VERSION 5.7 ;
BUSBITCHARS "[]" ;
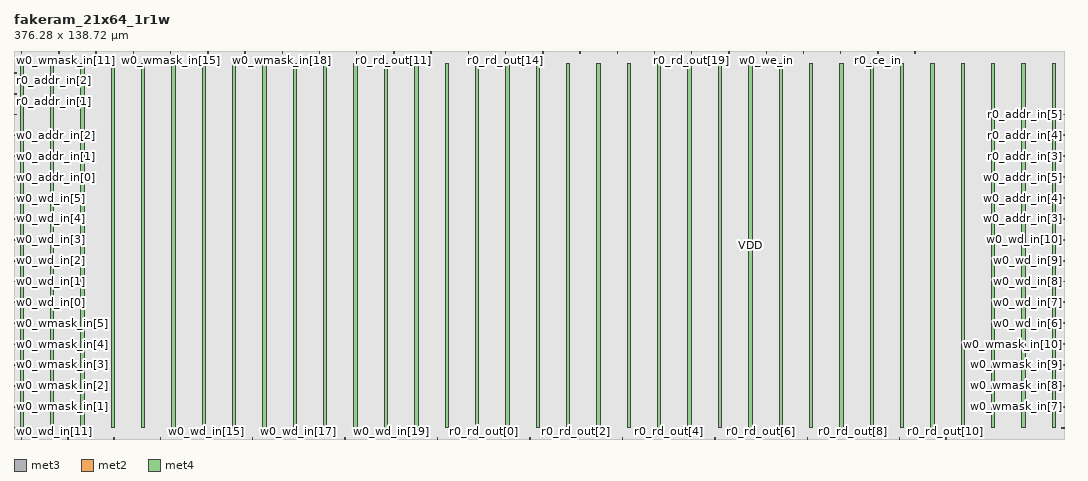
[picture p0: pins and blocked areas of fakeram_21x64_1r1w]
MACRO fakeram_21x64_1r1w
  FOREIGN fakeram_21x64_1r1w 0 0 ;
  SYMMETRY X Y R90 ;
  SIZE 376.280 BY 138.720 ;
  CLASS BLOCK ;
  PIN w0_wmask_in[0]
    DIRECTION INPUT ;
    USE SIGNAL ;
    SHAPE ABUTMENT ;
    PORT
      LAYER met3 ;
      RECT 0.000 3.930 0.900 4.230 ;
    END
  END w0_wmask_in[0]
  PIN w0_wmask_in[1]
    DIRECTION INPUT ;
    USE SIGNAL ;
    SHAPE ABUTMENT ;
    PORT
      LAYER met3 ;
      RECT 0.000 11.410 0.900 11.710 ;
    END
  END w0_wmask_in[1]
  PIN w0_wmask_in[2]
    DIRECTION INPUT ;
    USE SIGNAL ;
    SHAPE ABUTMENT ;
    PORT
      LAYER met3 ;
      RECT 0.000 18.890 0.900 19.190 ;
    END
  END w0_wmask_in[2]
  PIN w0_wmask_in[3]
    DIRECTION INPUT ;
    USE SIGNAL ;
    SHAPE ABUTMENT ;
    PORT
      LAYER met3 ;
      RECT 0.000 26.370 0.900 26.670 ;
    END
  END w0_wmask_in[3]
  PIN w0_wmask_in[4]
    DIRECTION INPUT ;
    USE SIGNAL ;
    SHAPE ABUTMENT ;
    PORT
      LAYER met3 ;
      RECT 0.000 33.850 0.900 34.150 ;
    END
  END w0_wmask_in[4]
  PIN w0_wmask_in[5]
    DIRECTION INPUT ;
    USE SIGNAL ;
    SHAPE ABUTMENT ;
    PORT
      LAYER met3 ;
      RECT 0.000 41.330 0.900 41.630 ;
    END
  END w0_wmask_in[5]
  PIN w0_wmask_in[6]
    DIRECTION INPUT ;
    USE SIGNAL ;
    SHAPE ABUTMENT ;
    PORT
      LAYER met3 ;
      RECT 375.380 3.930 376.280 4.230 ;
    END
  END w0_wmask_in[6]
  PIN w0_wmask_in[7]
    DIRECTION INPUT ;
    USE SIGNAL ;
    SHAPE ABUTMENT ;
    PORT
      LAYER met3 ;
      RECT 375.380 11.410 376.280 11.710 ;
    END
  END w0_wmask_in[7]
  PIN w0_wmask_in[8]
    DIRECTION INPUT ;
    USE SIGNAL ;
    SHAPE ABUTMENT ;
    PORT
      LAYER met3 ;
      RECT 375.380 18.890 376.280 19.190 ;
    END
  END w0_wmask_in[8]
  PIN w0_wmask_in[9]
    DIRECTION INPUT ;
    USE SIGNAL ;
    SHAPE ABUTMENT ;
    PORT
      LAYER met3 ;
      RECT 375.380 26.370 376.280 26.670 ;
    END
  END w0_wmask_in[9]
  PIN w0_wmask_in[10]
    DIRECTION INPUT ;
    USE SIGNAL ;
    SHAPE ABUTMENT ;
    PORT
      LAYER met3 ;
      RECT 375.380 33.850 376.280 34.150 ;
    END
  END w0_wmask_in[10]
  PIN w0_wmask_in[11]
    DIRECTION INPUT ;
    USE SIGNAL ;
    SHAPE ABUTMENT ;
    PORT
      LAYER met2 ;
      RECT 2.690 138.300 2.830 138.720 ;
    END
  END w0_wmask_in[11]
  PIN w0_wmask_in[12]
    DIRECTION INPUT ;
    USE SIGNAL ;
    SHAPE ABUTMENT ;
    PORT
      LAYER met2 ;
      RECT 16.030 138.300 16.170 138.720 ;
    END
  END w0_wmask_in[12]
  PIN w0_wmask_in[13]
    DIRECTION INPUT ;
    USE SIGNAL ;
    SHAPE ABUTMENT ;
    PORT
      LAYER met2 ;
      RECT 29.370 138.300 29.510 138.720 ;
    END
  END w0_wmask_in[13]
  PIN w0_wmask_in[14]
    DIRECTION INPUT ;
    USE SIGNAL ;
    SHAPE ABUTMENT ;
    PORT
      LAYER met2 ;
      RECT 42.710 138.300 42.850 138.720 ;
    END
  END w0_wmask_in[14]
  PIN w0_wmask_in[15]
    DIRECTION INPUT ;
    USE SIGNAL ;
    SHAPE ABUTMENT ;
    PORT
      LAYER met2 ;
      RECT 56.050 138.300 56.190 138.720 ;
    END
  END w0_wmask_in[15]
  PIN w0_wmask_in[16]
    DIRECTION INPUT ;
    USE SIGNAL ;
    SHAPE ABUTMENT ;
    PORT
      LAYER met2 ;
      RECT 69.390 138.300 69.530 138.720 ;
    END
  END w0_wmask_in[16]
  PIN w0_wmask_in[17]
    DIRECTION INPUT ;
    USE SIGNAL ;
    SHAPE ABUTMENT ;
    PORT
      LAYER met2 ;
      RECT 82.730 138.300 82.870 138.720 ;
    END
  END w0_wmask_in[17]
  PIN w0_wmask_in[18]
    DIRECTION INPUT ;
    USE SIGNAL ;
    SHAPE ABUTMENT ;
    PORT
      LAYER met2 ;
      RECT 96.070 138.300 96.210 138.720 ;
    END
  END w0_wmask_in[18]
  PIN w0_wmask_in[19]
    DIRECTION INPUT ;
    USE SIGNAL ;
    SHAPE ABUTMENT ;
    PORT
      LAYER met2 ;
      RECT 109.410 138.300 109.550 138.720 ;
    END
  END w0_wmask_in[19]
  PIN w0_wmask_in[20]
    DIRECTION INPUT ;
    USE SIGNAL ;
    SHAPE ABUTMENT ;
    PORT
      LAYER met2 ;
      RECT 122.750 138.300 122.890 138.720 ;
    END
  END w0_wmask_in[20]
  PIN w0_wd_in[0]
    DIRECTION INPUT ;
    USE SIGNAL ;
    SHAPE ABUTMENT ;
    PORT
      LAYER met3 ;
      RECT 0.000 48.810 0.900 49.110 ;
    END
  END w0_wd_in[0]
  PIN w0_wd_in[1]
    DIRECTION INPUT ;
    USE SIGNAL ;
    SHAPE ABUTMENT ;
    PORT
      LAYER met3 ;
      RECT 0.000 56.290 0.900 56.590 ;
    END
  END w0_wd_in[1]
  PIN w0_wd_in[2]
    DIRECTION INPUT ;
    USE SIGNAL ;
    SHAPE ABUTMENT ;
    PORT
      LAYER met3 ;
      RECT 0.000 63.770 0.900 64.070 ;
    END
  END w0_wd_in[2]
  PIN w0_wd_in[3]
    DIRECTION INPUT ;
    USE SIGNAL ;
    SHAPE ABUTMENT ;
    PORT
      LAYER met3 ;
      RECT 0.000 71.250 0.900 71.550 ;
    END
  END w0_wd_in[3]
  PIN w0_wd_in[4]
    DIRECTION INPUT ;
    USE SIGNAL ;
    SHAPE ABUTMENT ;
    PORT
      LAYER met3 ;
      RECT 0.000 78.730 0.900 79.030 ;
    END
  END w0_wd_in[4]
  PIN w0_wd_in[5]
    DIRECTION INPUT ;
    USE SIGNAL ;
    SHAPE ABUTMENT ;
    PORT
      LAYER met3 ;
      RECT 0.000 86.210 0.900 86.510 ;
    END
  END w0_wd_in[5]
  PIN w0_wd_in[6]
    DIRECTION INPUT ;
    USE SIGNAL ;
    SHAPE ABUTMENT ;
    PORT
      LAYER met3 ;
      RECT 375.380 41.330 376.280 41.630 ;
    END
  END w0_wd_in[6]
  PIN w0_wd_in[7]
    DIRECTION INPUT ;
    USE SIGNAL ;
    SHAPE ABUTMENT ;
    PORT
      LAYER met3 ;
      RECT 375.380 48.810 376.280 49.110 ;
    END
  END w0_wd_in[7]
  PIN w0_wd_in[8]
    DIRECTION INPUT ;
    USE SIGNAL ;
    SHAPE ABUTMENT ;
    PORT
      LAYER met3 ;
      RECT 375.380 56.290 376.280 56.590 ;
    END
  END w0_wd_in[8]
  PIN w0_wd_in[9]
    DIRECTION INPUT ;
    USE SIGNAL ;
    SHAPE ABUTMENT ;
    PORT
      LAYER met3 ;
      RECT 375.380 63.770 376.280 64.070 ;
    END
  END w0_wd_in[9]
  PIN w0_wd_in[10]
    DIRECTION INPUT ;
    USE SIGNAL ;
    SHAPE ABUTMENT ;
    PORT
      LAYER met3 ;
      RECT 375.380 71.250 376.280 71.550 ;
    END
  END w0_wd_in[10]
  PIN w0_wd_in[11]
    DIRECTION OUTPUT ;
    USE SIGNAL ;
    SHAPE ABUTMENT ;
    PORT
      LAYER met2 ;
      RECT 2.690 0.000 2.830 0.420 ;
    END
  END w0_wd_in[11]
  PIN w0_wd_in[12]
    DIRECTION OUTPUT ;
    USE SIGNAL ;
    SHAPE ABUTMENT ;
    PORT
      LAYER met2 ;
      RECT 19.250 0.000 19.390 0.420 ;
    END
  END w0_wd_in[12]
  PIN w0_wd_in[13]
    DIRECTION OUTPUT ;
    USE SIGNAL ;
    SHAPE ABUTMENT ;
    PORT
      LAYER met2 ;
      RECT 35.810 0.000 35.950 0.420 ;
    END
  END w0_wd_in[13]
  PIN w0_wd_in[14]
    DIRECTION OUTPUT ;
    USE SIGNAL ;
    SHAPE ABUTMENT ;
    PORT
      LAYER met2 ;
      RECT 52.370 0.000 52.510 0.420 ;
    END
  END w0_wd_in[14]
  PIN w0_wd_in[15]
    DIRECTION OUTPUT ;
    USE SIGNAL ;
    SHAPE ABUTMENT ;
    PORT
      LAYER met2 ;
      RECT 68.930 0.000 69.070 0.420 ;
    END
  END w0_wd_in[15]
  PIN w0_wd_in[16]
    DIRECTION OUTPUT ;
    USE SIGNAL ;
    SHAPE ABUTMENT ;
    PORT
      LAYER met2 ;
      RECT 85.490 0.000 85.630 0.420 ;
    END
  END w0_wd_in[16]
  PIN w0_wd_in[17]
    DIRECTION OUTPUT ;
    USE SIGNAL ;
    SHAPE ABUTMENT ;
    PORT
      LAYER met2 ;
      RECT 102.050 0.000 102.190 0.420 ;
    END
  END w0_wd_in[17]
  PIN w0_wd_in[18]
    DIRECTION OUTPUT ;
    USE SIGNAL ;
    SHAPE ABUTMENT ;
    PORT
      LAYER met2 ;
      RECT 118.610 0.000 118.750 0.420 ;
    END
  END w0_wd_in[18]
  PIN w0_wd_in[19]
    DIRECTION OUTPUT ;
    USE SIGNAL ;
    SHAPE ABUTMENT ;
    PORT
      LAYER met2 ;
      RECT 135.170 0.000 135.310 0.420 ;
    END
  END w0_wd_in[19]
  PIN w0_wd_in[20]
    DIRECTION OUTPUT ;
    USE SIGNAL ;
    SHAPE ABUTMENT ;
    PORT
      LAYER met2 ;
      RECT 151.730 0.000 151.870 0.420 ;
    END
  END w0_wd_in[20]
  PIN r0_rd_out[0]
    DIRECTION OUTPUT ;
    USE SIGNAL ;
    SHAPE ABUTMENT ;
    PORT
      LAYER met2 ;
      RECT 168.290 0.000 168.430 0.420 ;
    END
  END r0_rd_out[0]
  PIN r0_rd_out[1]
    DIRECTION OUTPUT ;
    USE SIGNAL ;
    SHAPE ABUTMENT ;
    PORT
      LAYER met2 ;
      RECT 184.850 0.000 184.990 0.420 ;
    END
  END r0_rd_out[1]
  PIN r0_rd_out[2]
    DIRECTION OUTPUT ;
    USE SIGNAL ;
    SHAPE ABUTMENT ;
    PORT
      LAYER met2 ;
      RECT 201.410 0.000 201.550 0.420 ;
    END
  END r0_rd_out[2]
  PIN r0_rd_out[3]
    DIRECTION OUTPUT ;
    USE SIGNAL ;
    SHAPE ABUTMENT ;
    PORT
      LAYER met2 ;
      RECT 217.970 0.000 218.110 0.420 ;
    END
  END r0_rd_out[3]
  PIN r0_rd_out[4]
    DIRECTION OUTPUT ;
    USE SIGNAL ;
    SHAPE ABUTMENT ;
    PORT
      LAYER met2 ;
      RECT 234.530 0.000 234.670 0.420 ;
    END
  END r0_rd_out[4]
  PIN r0_rd_out[5]
    DIRECTION OUTPUT ;
    USE SIGNAL ;
    SHAPE ABUTMENT ;
    PORT
      LAYER met2 ;
      RECT 251.090 0.000 251.230 0.420 ;
    END
  END r0_rd_out[5]
  PIN r0_rd_out[6]
    DIRECTION OUTPUT ;
    USE SIGNAL ;
    SHAPE ABUTMENT ;
    PORT
      LAYER met2 ;
      RECT 267.650 0.000 267.790 0.420 ;
    END
  END r0_rd_out[6]
  PIN r0_rd_out[7]
    DIRECTION OUTPUT ;
    USE SIGNAL ;
    SHAPE ABUTMENT ;
    PORT
      LAYER met2 ;
      RECT 284.210 0.000 284.350 0.420 ;
    END
  END r0_rd_out[7]
  PIN r0_rd_out[8]
    DIRECTION OUTPUT ;
    USE SIGNAL ;
    SHAPE ABUTMENT ;
    PORT
      LAYER met2 ;
      RECT 300.770 0.000 300.910 0.420 ;
    END
  END r0_rd_out[8]
  PIN r0_rd_out[9]
    DIRECTION OUTPUT ;
    USE SIGNAL ;
    SHAPE ABUTMENT ;
    PORT
      LAYER met2 ;
      RECT 317.330 0.000 317.470 0.420 ;
    END
  END r0_rd_out[9]
  PIN r0_rd_out[10]
    DIRECTION OUTPUT ;
    USE SIGNAL ;
    SHAPE ABUTMENT ;
    PORT
      LAYER met2 ;
      RECT 333.890 0.000 334.030 0.420 ;
    END
  END r0_rd_out[10]
  PIN r0_rd_out[11]
    DIRECTION OUTPUT ;
    USE SIGNAL ;
    SHAPE ABUTMENT ;
    PORT
      LAYER met2 ;
      RECT 136.090 138.300 136.230 138.720 ;
    END
  END r0_rd_out[11]
  PIN r0_rd_out[12]
    DIRECTION OUTPUT ;
    USE SIGNAL ;
    SHAPE ABUTMENT ;
    PORT
      LAYER met2 ;
      RECT 149.430 138.300 149.570 138.720 ;
    END
  END r0_rd_out[12]
  PIN r0_rd_out[13]
    DIRECTION OUTPUT ;
    USE SIGNAL ;
    SHAPE ABUTMENT ;
    PORT
      LAYER met2 ;
      RECT 162.770 138.300 162.910 138.720 ;
    END
  END r0_rd_out[13]
  PIN r0_rd_out[14]
    DIRECTION OUTPUT ;
    USE SIGNAL ;
    SHAPE ABUTMENT ;
    PORT
      LAYER met2 ;
      RECT 176.110 138.300 176.250 138.720 ;
    END
  END r0_rd_out[14]
  PIN r0_rd_out[15]
    DIRECTION OUTPUT ;
    USE SIGNAL ;
    SHAPE ABUTMENT ;
    PORT
      LAYER met2 ;
      RECT 189.450 138.300 189.590 138.720 ;
    END
  END r0_rd_out[15]
  PIN r0_rd_out[16]
    DIRECTION OUTPUT ;
    USE SIGNAL ;
    SHAPE ABUTMENT ;
    PORT
      LAYER met2 ;
      RECT 202.790 138.300 202.930 138.720 ;
    END
  END r0_rd_out[16]
  PIN r0_rd_out[17]
    DIRECTION OUTPUT ;
    USE SIGNAL ;
    SHAPE ABUTMENT ;
    PORT
      LAYER met2 ;
      RECT 216.130 138.300 216.270 138.720 ;
    END
  END r0_rd_out[17]
  PIN r0_rd_out[18]
    DIRECTION OUTPUT ;
    USE SIGNAL ;
    SHAPE ABUTMENT ;
    PORT
      LAYER met2 ;
      RECT 229.470 138.300 229.610 138.720 ;
    END
  END r0_rd_out[18]
  PIN r0_rd_out[19]
    DIRECTION OUTPUT ;
    USE SIGNAL ;
    SHAPE ABUTMENT ;
    PORT
      LAYER met2 ;
      RECT 242.810 138.300 242.950 138.720 ;
    END
  END r0_rd_out[19]
  PIN r0_rd_out[20]
    DIRECTION OUTPUT ;
    USE SIGNAL ;
    SHAPE ABUTMENT ;
    PORT
      LAYER met2 ;
      RECT 256.150 138.300 256.290 138.720 ;
    END
  END r0_rd_out[20]
  PIN w0_addr_in[0]
    DIRECTION INPUT ;
    USE SIGNAL ;
    SHAPE ABUTMENT ;
    PORT
      LAYER met3 ;
      RECT 0.000 93.690 0.900 93.990 ;
    END
  END w0_addr_in[0]
  PIN w0_addr_in[1]
    DIRECTION INPUT ;
    USE SIGNAL ;
    SHAPE ABUTMENT ;
    PORT
      LAYER met3 ;
      RECT 0.000 101.170 0.900 101.470 ;
    END
  END w0_addr_in[1]
  PIN w0_addr_in[2]
    DIRECTION INPUT ;
    USE SIGNAL ;
    SHAPE ABUTMENT ;
    PORT
      LAYER met3 ;
      RECT 0.000 108.650 0.900 108.950 ;
    END
  END w0_addr_in[2]
  PIN w0_addr_in[3]
    DIRECTION INPUT ;
    USE SIGNAL ;
    SHAPE ABUTMENT ;
    PORT
      LAYER met3 ;
      RECT 375.380 78.730 376.280 79.030 ;
    END
  END w0_addr_in[3]
  PIN w0_addr_in[4]
    DIRECTION INPUT ;
    USE SIGNAL ;
    SHAPE ABUTMENT ;
    PORT
      LAYER met3 ;
      RECT 375.380 86.210 376.280 86.510 ;
    END
  END w0_addr_in[4]
  PIN w0_addr_in[5]
    DIRECTION INPUT ;
    USE SIGNAL ;
    SHAPE ABUTMENT ;
    PORT
      LAYER met3 ;
      RECT 375.380 93.690 376.280 93.990 ;
    END
  END w0_addr_in[5]
  PIN r0_addr_in[0]
    DIRECTION INPUT ;
    USE SIGNAL ;
    SHAPE ABUTMENT ;
    PORT
      LAYER met3 ;
      RECT 0.000 116.130 0.900 116.430 ;
    END
  END r0_addr_in[0]
  PIN r0_addr_in[1]
    DIRECTION INPUT ;
    USE SIGNAL ;
    SHAPE ABUTMENT ;
    PORT
      LAYER met3 ;
      RECT 0.000 123.610 0.900 123.910 ;
    END
  END r0_addr_in[1]
  PIN r0_addr_in[2]
    DIRECTION INPUT ;
    USE SIGNAL ;
    SHAPE ABUTMENT ;
    PORT
      LAYER met3 ;
      RECT 0.000 131.090 0.900 131.390 ;
    END
  END r0_addr_in[2]
  PIN r0_addr_in[3]
    DIRECTION INPUT ;
    USE SIGNAL ;
    SHAPE ABUTMENT ;
    PORT
      LAYER met3 ;
      RECT 375.380 101.170 376.280 101.470 ;
    END
  END r0_addr_in[3]
  PIN r0_addr_in[4]
    DIRECTION INPUT ;
    USE SIGNAL ;
    SHAPE ABUTMENT ;
    PORT
      LAYER met3 ;
      RECT 375.380 108.650 376.280 108.950 ;
    END
  END r0_addr_in[4]
  PIN r0_addr_in[5]
    DIRECTION INPUT ;
    USE SIGNAL ;
    SHAPE ABUTMENT ;
    PORT
      LAYER met3 ;
      RECT 375.380 116.130 376.280 116.430 ;
    END
  END r0_addr_in[5]
  PIN w0_we_in
    DIRECTION INPUT ;
    USE SIGNAL ;
    SHAPE ABUTMENT ;
    PORT
      LAYER met2 ;
      RECT 269.490 138.300 269.630 138.720 ;
    END
  END w0_we_in
  PIN w0_ce_in
    DIRECTION INPUT ;
    USE SIGNAL ;
    SHAPE ABUTMENT ;
    PORT
      LAYER met2 ;
      RECT 282.830 138.300 282.970 138.720 ;
    END
  END w0_ce_in
  PIN w0_clk
    DIRECTION INPUT ;
    USE SIGNAL ;
    SHAPE ABUTMENT ;
    PORT
      LAYER met2 ;
      RECT 296.170 138.300 296.310 138.720 ;
    END
  END w0_clk
  PIN r0_ce_in
    DIRECTION INPUT ;
    USE SIGNAL ;
    SHAPE ABUTMENT ;
    PORT
      LAYER met2 ;
      RECT 309.510 138.300 309.650 138.720 ;
    END
  END r0_ce_in
  PIN r0_clk
    DIRECTION INPUT ;
    USE SIGNAL ;
    SHAPE ABUTMENT ;
    PORT
      LAYER met2 ;
      RECT 322.850 138.300 322.990 138.720 ;
    END
  END r0_clk
  PIN VSS
    DIRECTION INOUT ;
    USE GROUND ;
    PORT
      LAYER met4 ;
      RECT 2.160 4.080 3.360 134.640 ;
      RECT 13.040 4.080 14.240 134.640 ;
      RECT 23.920 4.080 25.120 134.640 ;
      RECT 34.800 4.080 36.000 134.640 ;
      RECT 45.680 4.080 46.880 134.640 ;
      RECT 56.560 4.080 57.760 134.640 ;
      RECT 67.440 4.080 68.640 134.640 ;
      RECT 78.320 4.080 79.520 134.640 ;
      RECT 89.200 4.080 90.400 134.640 ;
      RECT 100.080 4.080 101.280 134.640 ;
      RECT 110.960 4.080 112.160 134.640 ;
      RECT 121.840 4.080 123.040 134.640 ;
      RECT 132.720 4.080 133.920 134.640 ;
      RECT 143.600 4.080 144.800 134.640 ;
      RECT 154.480 4.080 155.680 134.640 ;
      RECT 165.360 4.080 166.560 134.640 ;
      RECT 176.240 4.080 177.440 134.640 ;
      RECT 187.120 4.080 188.320 134.640 ;
      RECT 198.000 4.080 199.200 134.640 ;
      RECT 208.880 4.080 210.080 134.640 ;
      RECT 219.760 4.080 220.960 134.640 ;
      RECT 230.640 4.080 231.840 134.640 ;
      RECT 241.520 4.080 242.720 134.640 ;
      RECT 252.400 4.080 253.600 134.640 ;
      RECT 263.280 4.080 264.480 134.640 ;
      RECT 274.160 4.080 275.360 134.640 ;
      RECT 285.040 4.080 286.240 134.640 ;
      RECT 295.920 4.080 297.120 134.640 ;
      RECT 306.800 4.080 308.000 134.640 ;
      RECT 317.680 4.080 318.880 134.640 ;
      RECT 328.560 4.080 329.760 134.640 ;
      RECT 339.440 4.080 340.640 134.640 ;
      RECT 350.320 4.080 351.520 134.640 ;
      RECT 361.200 4.080 362.400 134.640 ;
      RECT 372.080 4.080 373.280 134.640 ;
    END
  END VSS
  PIN VDD
    DIRECTION INOUT ;
    USE POWER ;
    PORT
      LAYER met4 ;
      RECT 2.160 4.080 3.360 134.640 ;
      RECT 13.040 4.080 14.240 134.640 ;
      RECT 23.920 4.080 25.120 134.640 ;
      RECT 34.800 4.080 36.000 134.640 ;
      RECT 45.680 4.080 46.880 134.640 ;
      RECT 56.560 4.080 57.760 134.640 ;
      RECT 67.440 4.080 68.640 134.640 ;
      RECT 78.320 4.080 79.520 134.640 ;
      RECT 89.200 4.080 90.400 134.640 ;
      RECT 100.080 4.080 101.280 134.640 ;
      RECT 110.960 4.080 112.160 134.640 ;
      RECT 121.840 4.080 123.040 134.640 ;
      RECT 132.720 4.080 133.920 134.640 ;
      RECT 143.600 4.080 144.800 134.640 ;
      RECT 154.480 4.080 155.680 134.640 ;
      RECT 165.360 4.080 166.560 134.640 ;
      RECT 176.240 4.080 177.440 134.640 ;
      RECT 187.120 4.080 188.320 134.640 ;
      RECT 198.000 4.080 199.200 134.640 ;
      RECT 208.880 4.080 210.080 134.640 ;
      RECT 219.760 4.080 220.960 134.640 ;
      RECT 230.640 4.080 231.840 134.640 ;
      RECT 241.520 4.080 242.720 134.640 ;
      RECT 252.400 4.080 253.600 134.640 ;
      RECT 263.280 4.080 264.480 134.640 ;
      RECT 274.160 4.080 275.360 134.640 ;
      RECT 285.040 4.080 286.240 134.640 ;
      RECT 295.920 4.080 297.120 134.640 ;
      RECT 306.800 4.080 308.000 134.640 ;
      RECT 317.680 4.080 318.880 134.640 ;
      RECT 328.560 4.080 329.760 134.640 ;
      RECT 339.440 4.080 340.640 134.640 ;
      RECT 350.320 4.080 351.520 134.640 ;
      RECT 361.200 4.080 362.400 134.640 ;
      RECT 372.080 4.080 373.280 134.640 ;
    END
  END VDD
  OBS
    LAYER met1 ;
    RECT 0 0 376.280 138.720 ;
    LAYER met2 ;
    RECT 0 0 376.280 138.720 ;
    LAYER met3 ;
    RECT 0 0 376.280 138.720 ;
    LAYER met4 ;
    RECT 0 0 376.280 138.720 ;
  END
END fakeram_21x64_1r1w

END LIBRARY
